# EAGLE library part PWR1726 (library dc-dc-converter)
DC-DC CONVERTER

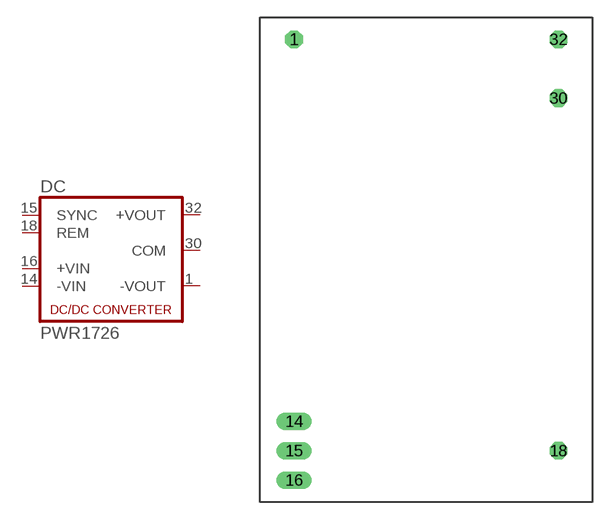
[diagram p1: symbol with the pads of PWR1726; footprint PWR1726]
Designator prefix DC

## PWR1726 (MPN: PWR1726AC; OC_FARNELL: 1694799; OC_NEWARK: 87K4872)  [PWR1726]
1  -VOUT  pas
14  -VIN  pas
15  SYNC  pas
16  +VIN  pas
18  REM  pas
30  COM  pas
32  +VOUT  pas

## Footprint PWR1726 (pad centres in mm)
DC-DC CONVERTER
drill 1.016 octagon: 1 -11.43,19.05; 18 11.43,-16.51; 30 11.43,13.97; 32 11.43,19.05
drill 1.016 long: 14 -11.43,-13.97; 15 -11.43,-16.51; 16 -11.43,-19.05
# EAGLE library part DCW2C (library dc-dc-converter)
DC-DC CONVERTER

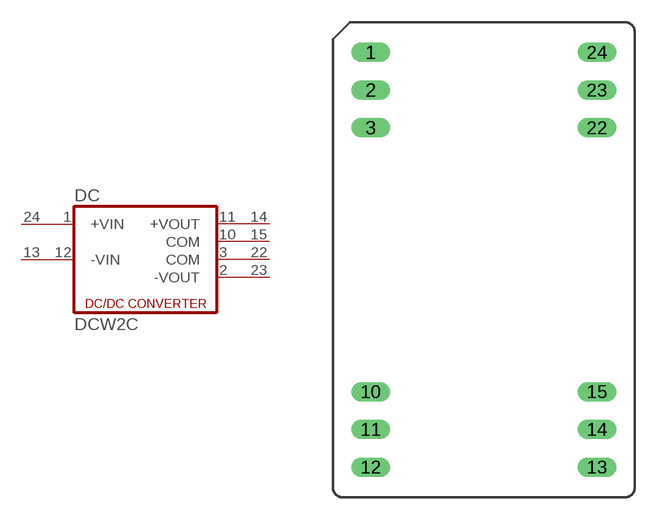
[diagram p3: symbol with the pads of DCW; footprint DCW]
Designator prefix DC

## DCW2C (OC_FARNELL: unknown; OC_NEWARK: unknown)  [DCW]
1  +VIN  pas
2  -VOUT  pas
3  COM  pas
10  COM  pas
11  +VOUT  pas
12  -VIN  pas
13  -VIN1  pas
14  +VOUT1  pas
15  COM1  pas
22  COM2  pas
23  -VOUT1  pas
24  +VIN1  pas

## Footprint DCW (pad centres in mm)
DC-DC CONVERTER
drill 0.813 long: 1 -7.62,13.97; 2 -7.62,11.43; 3 -7.62,8.89; 10 -7.62,-8.89; 11 -7.62,-11.43; 12 -7.62,-13.97; 13 7.62,-13.97; 14 7.62,-11.43; 15 7.62,-8.89; 22 7.62,8.89; 23 7.62,11.43; 24 7.62,13.97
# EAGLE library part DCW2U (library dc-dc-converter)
DC-DC CONVERTER

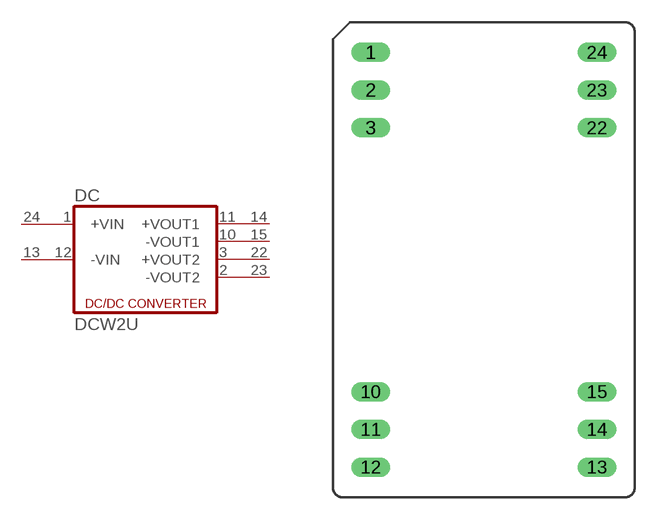
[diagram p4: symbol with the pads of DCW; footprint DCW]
Designator prefix DC

## DCW2U (OC_FARNELL: unknown; OC_NEWARK: unknown)  [DCW]
1  +VIN  pas
2  -VOUT2  pas
3  +VOUT2  pas
10  -VOUT1  pas
11  +VOUT1  pas
12  -VIN  pas
13  -VIN1  pas
14  +VOUT  pas
15  -VOUT  pas
22  +VOUT  pas
23  -VOUT  pas
24  +VIN1  pas

## Footprint DCW (pad centres in mm)
DC-DC CONVERTER
drill 0.813 long: 1 -7.62,13.97; 2 -7.62,11.43; 3 -7.62,8.89; 10 -7.62,-8.89; 11 -7.62,-11.43; 12 -7.62,-13.97; 13 7.62,-13.97; 14 7.62,-11.43; 15 7.62,-8.89; 22 7.62,8.89; 23 7.62,11.43; 24 7.62,13.97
